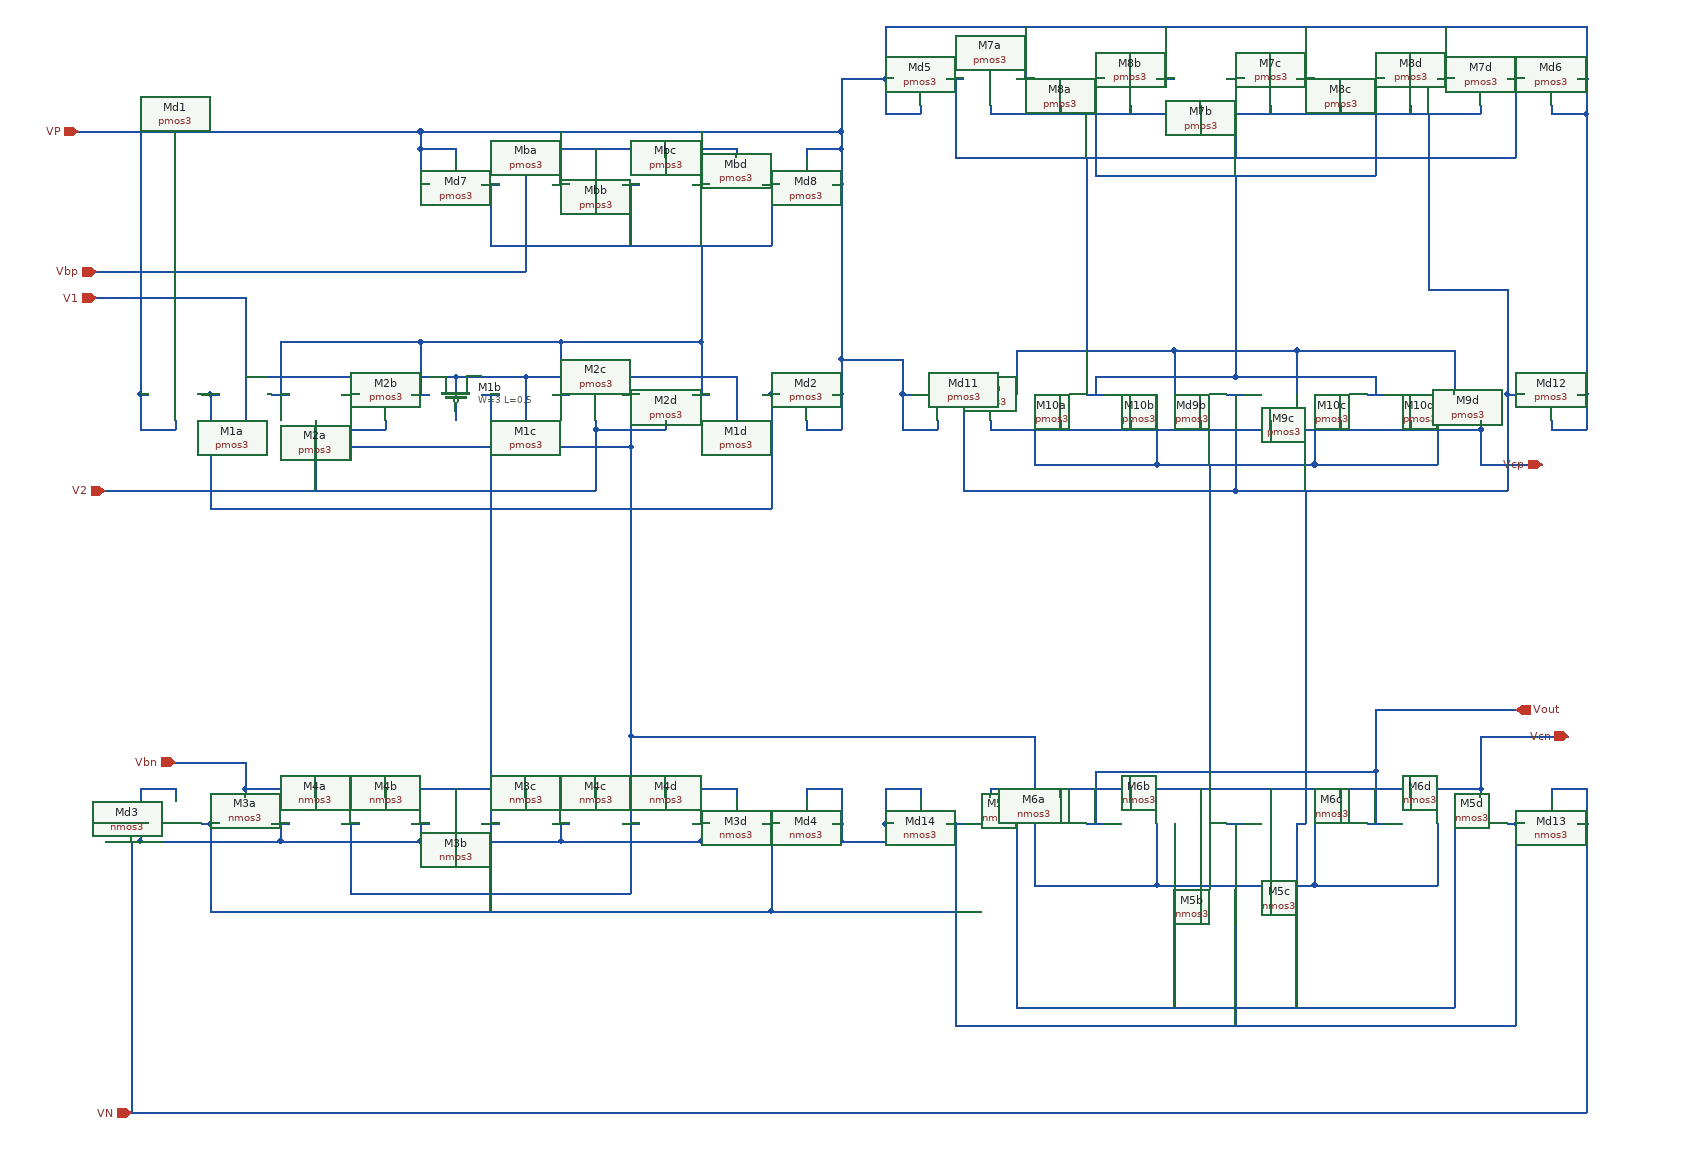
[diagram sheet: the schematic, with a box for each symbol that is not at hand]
v {xschem version=2.9.9 file_version=1.2 }
G {}
K {}
V {}
S {}
E {}
N 240 -350 250 -350 { lab=#net1}
N 280 -390 280 -380 { lab=Vbn}
N 280 -390 840 -390 { lab=Vbn}
N 840 -390 840 -380 { lab=Vbn}
N 760 -390 760 -380 { lab=Vbn}
N 680 -390 680 -380 { lab=Vbn}
N 600 -390 600 -380 { lab=Vbn}
N 520 -390 520 -380 { lab=Vbn}
N 440 -390 440 -380 { lab=Vbn}
N 360 -390 360 -380 { lab=Vbn}
N 310 -350 330 -350 { lab=VP}
N 390 -350 410 -350 { lab=#net2}
N 470 -350 490 -350 { lab=VP}
N 550 -350 570 -350 { lab=#net1}
N 630 -350 650 -350 { lab=VP}
N 710 -350 730 -350 { lab=#net2}
N 790 -350 810 -350 { lab=VP}
N 240 -250 870 -250 { lab=#net1}
N 240 -350 240 -250 { lab=#net1}
N 870 -350 880 -350 { lab=#net1}
N 880 -350 880 -250 { lab=#net1}
N 870 -250 880 -250 { lab=#net1}
N 400 -350 400 -270 { lab=#net2}
N 720 -350 720 -270 { lab=#net2}
N 560 -350 560 -250 { lab=#net1}
N 280 -420 280 -390 { lab=Vbn}
N 200 -420 280 -420 { lab=Vbn}
N 400 -270 720 -270 { lab=#net2}
N 230 -350 240 -350 { lab=#net1}
N 200 -390 200 -380 { lab=VP}
N 160 -390 200 -390 { lab=VP}
N 160 -390 160 -350 { lab=VP}
N 160 -350 170 -350 { lab=VP}
N 160 -350 160 -330 { lab=VP}
N 880 -350 890 -350 { lab=#net1}
N 950 -350 960 -350 { lab=VP}
N 960 -390 960 -350 { lab=VP}
N 920 -390 960 -390 { lab=VP}
N 920 -390 920 -380 { lab=VP}
N 960 -350 960 -330 { lab=VP}
N 1090 -350 1100 -350 { lab=#net1}
N 1130 -390 1130 -380 { lab=Vcn}
N 1130 -390 1690 -390 { lab=Vcn}
N 1690 -390 1690 -380 { lab=Vcn}
N 1610 -390 1610 -380 { lab=Vcn}
N 1530 -390 1530 -380 { lab=Vcn}
N 1450 -390 1450 -380 { lab=Vcn}
N 1370 -390 1370 -380 { lab=Vcn}
N 1290 -390 1290 -380 { lab=Vcn}
N 1210 -390 1210 -380 { lab=Vcn}
N 1720 -350 1730 -350 { lab=#net1}
N 1080 -350 1090 -350 { lab=#net1}
N 1050 -390 1050 -380 { lab=VP}
N 1010 -390 1050 -390 { lab=VP}
N 1010 -390 1010 -350 { lab=VP}
N 1010 -350 1020 -350 { lab=VP}
N 1010 -350 1010 -330 { lab=VP}
N 1730 -350 1740 -350 { lab=#net1}
N 1800 -350 1810 -350 { lab=VP}
N 1810 -390 1810 -350 { lab=VP}
N 1770 -390 1810 -390 { lab=VP}
N 1770 -390 1770 -380 { lab=VP}
N 1810 -350 1810 -330 { lab=VP}
N 1160 -350 1160 -320 { lab=#net3}
N 1660 -350 1660 -320 { lab=#net3}
N 1090 -350 1090 -130 { lab=#net1}
N 1090 -130 1090 -120 { lab=#net1}
N 1160 -320 1160 -140 { lab=#net3}
N 1660 -320 1660 -140 { lab=#net3}
N 1160 -140 1660 -140 { lab=#net3}
N 1400 -350 1420 -350 { lab=#net1}
N 1240 -350 1260 -350 { lab=Vout}
N 1560 -350 1580 -350 { lab=Vout}
N 1320 -350 1320 -280 { lab=#net2}
N 1180 -280 1320 -280 { lab=#net2}
N 1180 -350 1180 -280 { lab=#net2}
N 1180 -450 1180 -350 { lab=#net2}
N 1690 -450 1690 -390 { lab=Vcn}
N 1690 -450 1790 -450 { lab=Vcn}
N 1500 -350 1500 -280 { lab=#net2}
N 1500 -280 1640 -280 { lab=#net2}
N 1640 -350 1640 -280 { lab=#net2}
N 1320 -280 1500 -280 { lab=#net2}
N 1570 -410 1570 -350 { lab=Vout}
N 1250 -410 1570 -410 { lab=Vout}
N 1250 -410 1250 -350 { lab=Vout}
N 1030 -450 1090 -450 { lab=#net2}
N 1490 -570 1490 -520 { lab=#net3}
N 1570 -480 1570 -410 { lab=Vout}
N 1570 -480 1730 -480 { lab=Vout}
N 1730 -350 1730 -120 { lab=#net1}
N 1090 -120 1730 -120 { lab=#net1}
N 720 -450 1030 -450 { lab=#net2}
N 720 -450 720 -350 { lab=#net2}
N 1130 -810 1130 -800 { lab=Vcp}
N 1210 -810 1210 -800 { lab=Vcp}
N 1290 -810 1290 -800 { lab=Vcp}
N 1370 -810 1370 -800 { lab=Vcp}
N 1450 -810 1450 -800 { lab=Vcp}
N 1530 -810 1530 -800 { lab=Vcp}
N 1610 -810 1610 -800 { lab=Vcp}
N 1690 -810 1690 -800 { lab=Vcp}
N 1130 -800 1690 -800 { lab=Vcp}
N 1400 -840 1420 -840 { lab=#net3}
N 1240 -840 1260 -840 { lab=#net4}
N 1560 -840 1580 -840 { lab=#net4}
N 1320 -840 1320 -760 { lab=Vout}
N 1320 -760 1500 -760 { lab=Vout}
N 1500 -840 1500 -760 { lab=Vout}
N 1180 -840 1180 -760 { lab=Vout}
N 1180 -760 1320 -760 { lab=Vout}
N 1500 -760 1640 -760 { lab=Vout}
N 1640 -840 1640 -760 { lab=Vout}
N 1250 -860 1250 -840 { lab=#net4}
N 1250 -860 1410 -860 { lab=#net4}
N 1410 -860 1570 -860 { lab=#net4}
N 1570 -860 1570 -840 { lab=#net4}
N 1410 -950 1410 -860 { lab=#net4}
N 1340 -350 1340 -140 { lab=#net3}
N 1480 -350 1480 -140 { lab=#net3}
N 1410 -350 1410 -120 { lab=#net1}
N 1480 -350 1490 -350 { lab=#net3}
N 1490 -520 1490 -350 { lab=#net3}
N 880 -250 1090 -250 { lab=#net1}
N 1090 -450 1180 -450 { lab=#net2}
N 1410 -840 1410 -780 { lab=#net3}
N 1720 -840 1720 -780 { lab=#net3}
N 1480 -890 1480 -840 { lab=#net5}
N 1480 -890 1660 -890 { lab=#net5}
N 1660 -890 1660 -840 { lab=#net5}
N 1340 -890 1340 -840 { lab=#net5}
N 1340 -890 1480 -890 { lab=#net5}
N 1100 -840 1100 -780 { lab=#net3}
N 1160 -890 1160 -840 { lab=#net5}
N 1160 -890 1340 -890 { lab=#net5}
N 1100 -780 1100 -730 { lab=#net3}
N 1100 -730 1410 -730 { lab=#net3}
N 1410 -730 1720 -730 { lab=#net3}
N 1720 -780 1720 -730 { lab=#net3}
N 1410 -780 1410 -730 { lab=#net3}
N 1380 -760 1380 -680 { lab=Vout}
N 1490 -730 1490 -640 { lab=#net3}
N 1690 -800 1690 -760 { lab=Vcp}
N 1690 -760 1760 -760 { lab=Vcp}
N 1070 -810 1070 -800 { lab=VP}
N 1030 -800 1070 -800 { lab=VP}
N 1030 -840 1030 -800 { lab=VP}
N 1030 -840 1040 -840 { lab=VP}
N 1030 -880 1030 -840 { lab=VP}
N 1720 -840 1740 -840 { lab=#net3}
N 1770 -810 1770 -800 { lab=VP}
N 1770 -800 1810 -800 { lab=VP}
N 1810 -840 1810 -800 { lab=VP}
N 1800 -840 1810 -840 { lab=VP}
N 1810 -860 1810 -840 { lab=VP}
N 1810 -880 1810 -860 { lab=VP}
N 1380 -670 1380 -410 { lab=Vout}
N 1380 -680 1380 -670 { lab=Vout}
N 1490 -640 1490 -570 { lab=#net3}
N 1720 -930 1720 -840 { lab=#net3}
N 1720 -960 1720 -930 { lab=#net3}
N 1240 -1040 1240 -890 { lab=#net5}
N 1400 -1200 1420 -1200 { lab=#net5}
N 1320 -1200 1340 -1200 { lab=VP}
N 1240 -1200 1260 -1200 { lab=#net4}
N 1160 -1200 1180 -1200 { lab=VP}
N 1480 -1200 1500 -1200 { lab=VP}
N 1560 -1200 1580 -1200 { lab=#net4}
N 1640 -1200 1660 -1200 { lab=VP}
N 1130 -1170 1130 -1160 { lab=#net3}
N 1130 -1160 1690 -1160 { lab=#net3}
N 1690 -1170 1690 -1160 { lab=#net3}
N 1610 -1170 1610 -1160 { lab=#net3}
N 1530 -1170 1530 -1160 { lab=#net3}
N 1450 -1170 1450 -1160 { lab=#net3}
N 1370 -1170 1370 -1160 { lab=#net3}
N 1290 -1170 1290 -1160 { lab=#net3}
N 1210 -1170 1210 -1160 { lab=#net3}
N 1170 -1260 1170 -1200 { lab=VP}
N 1330 -1260 1330 -1200 { lab=VP}
N 1490 -1260 1490 -1200 { lab=VP}
N 1650 -1260 1650 -1200 { lab=VP}
N 1570 -1200 1570 -1130 { lab=#net4}
N 1410 -1200 1410 -1130 { lab=#net5}
N 1250 -1200 1250 -1130 { lab=#net4}
N 1090 -1200 1100 -1200 { lab=#net5}
N 1090 -1200 1090 -1130 { lab=#net5}
N 1720 -1200 1730 -1200 { lab=#net5}
N 1730 -1200 1730 -1130 { lab=#net5}
N 1730 -1130 1730 -1110 { lab=#net5}
N 1090 -1110 1730 -1110 { lab=#net5}
N 1090 -1130 1090 -1110 { lab=#net5}
N 1410 -1130 1410 -1110 { lab=#net5}
N 1570 -1130 1570 -1090 { lab=#net4}
N 1250 -1090 1570 -1090 { lab=#net4}
N 1250 -1130 1250 -1090 { lab=#net4}
N 1410 -1090 1410 -1040 { lab=#net4}
N 1630 -1160 1630 -1030 { lab=#net3}
N 1080 -1200 1090 -1200 { lab=#net5}
N 1730 -1200 1740 -1200 { lab=#net5}
N 1050 -1170 1050 -1160 { lab=VP}
N 1010 -1160 1050 -1160 { lab=VP}
N 1010 -1200 1010 -1160 { lab=VP}
N 1010 -1200 1020 -1200 { lab=VP}
N 1010 -1250 1010 -1200 { lab=VP}
N 1770 -1170 1770 -1160 { lab=VP}
N 1770 -1160 1810 -1160 { lab=VP}
N 1810 -1200 1810 -1160 { lab=VP}
N 1800 -1200 1810 -1200 { lab=VP}
N 1810 -1260 1810 -1200 { lab=VP}
N 1630 -1030 1630 -960 { lab=#net3}
N 1630 -960 1720 -960 { lab=#net3}
N 1410 -1040 1410 -950 { lab=#net4}
N 1240 -1110 1240 -1040 { lab=#net5}
N 550 -840 570 -840 { lab=#net1}
N 470 -840 490 -840 { lab=#net6}
N 390 -840 410 -840 { lab=#net2}
N 310 -840 330 -840 { lab=#net6}
N 630 -840 650 -840 { lab=#net6}
N 710 -840 730 -840 { lab=#net2}
N 790 -840 810 -840 { lab=#net6}
N 760 -810 760 -800 { lab=V2}
N 680 -810 680 -800 { lab=V2}
N 440 -810 440 -800 { lab=V2}
N 360 -810 360 -800 { lab=V2}
N 320 -900 320 -840 { lab=#net6}
N 480 -900 480 -840 { lab=#net6}
N 640 -900 640 -840 { lab=#net6}
N 800 -900 800 -840 { lab=#net6}
N 240 -840 250 -840 { lab=#net1}
N 870 -840 880 -840 { lab=#net1}
N 230 -840 240 -840 { lab=#net1}
N 880 -840 890 -840 { lab=#net1}
N 200 -810 200 -800 { lab=VP}
N 160 -800 200 -800 { lab=VP}
N 160 -840 160 -800 { lab=VP}
N 160 -840 170 -840 { lab=VP}
N 920 -810 920 -800 { lab=VP}
N 920 -800 960 -800 { lab=VP}
N 960 -840 960 -800 { lab=VP}
N 950 -840 960 -840 { lab=VP}
N 360 -800 440 -800 { lab=V2}
N 680 -800 760 -800 { lab=V2}
N 280 -950 280 -810 { lab=V1}
N 110 -950 280 -950 { lab=V1}
N 680 -800 680 -730 { lab=V2}
N 120 -730 680 -730 { lab=V2}
N 360 -800 360 -730 { lab=V2}
N 320 -900 480 -900 { lab=#net6}
N 480 -900 640 -900 { lab=#net6}
N 640 -900 800 -900 { lab=#net6}
N 240 -840 240 -790 { lab=#net1}
N 600 -860 600 -810 { lab=V1}
N 520 -860 600 -860 { lab=V1}
N 560 -840 560 -790 { lab=#net1}
N 880 -840 880 -790 { lab=#net1}
N 400 -840 400 -780 { lab=#net2}
N 400 -780 720 -780 { lab=#net2}
N 720 -840 720 -780 { lab=#net2}
N 240 -790 240 -760 { lab=#net1}
N 240 -760 240 -710 { lab=#net1}
N 240 -710 880 -710 { lab=#net1}
N 880 -790 880 -710 { lab=#net1}
N 720 -780 720 -640 { lab=#net2}
N 560 -790 560 -710 { lab=#net1}
N 960 -880 960 -840 { lab=VP}
N 160 -880 160 -840 { lab=VP}
N 520 -860 520 -820 { lab=V1}
N 840 -860 840 -810 { lab=V1}
N 600 -860 840 -860 { lab=V1}
N 280 -860 520 -860 { lab=V1}
N 720 -640 720 -620 { lab=#net2}
N 720 -620 720 -450 { lab=#net2}
N 560 -630 560 -350 { lab=#net1}
N 560 -710 560 -630 { lab=#net1}
N 520 -1120 520 -1110 { lab=VP}
N 600 -1120 600 -1110 { lab=Vbp}
N 680 -1120 680 -1110 { lab=Vbp}
N 760 -1120 760 -1110 { lab=Vbp}
N 840 -1120 840 -1110 { lab=Vbp}
N 600 -1120 840 -1120 { lab=Vbp}
N 630 -1080 650 -1080 { lab=VP}
N 710 -1080 730 -1080 { lab=#net6}
N 790 -1080 810 -1080 { lab=VP}
N 870 -1080 890 -1080 { lab=#net6}
N 550 -1080 570 -1080 { lab=#net6}
N 480 -1120 520 -1120 { lab=VP}
N 480 -1120 480 -1080 { lab=VP}
N 480 -1080 490 -1080 { lab=VP}
N 920 -1120 920 -1110 { lab=VP}
N 920 -1120 960 -1120 { lab=VP}
N 960 -1120 960 -1080 { lab=VP}
N 950 -1080 960 -1080 { lab=VP}
N 720 -1080 720 -1060 { lab=#net6}
N 800 -1140 800 -1080 { lab=VP}
N 640 -1130 640 -1080 { lab=VP}
N 560 -1080 560 -1030 { lab=#net6}
N 880 -1080 880 -1030 { lab=#net6}
N 960 -1140 960 -1120 { lab=VP}
N 480 -1140 480 -1120 { lab=VP}
N 640 -1140 640 -1130 { lab=VP}
N 560 -1030 560 -1010 { lab=#net6}
N 560 -1010 880 -1010 { lab=#net6}
N 880 -1030 880 -1010 { lab=#net6}
N 720 -1060 720 -1010 { lab=#net6}
N 480 -980 600 -980 { lab=Vbp}
N 600 -1110 600 -980 { lab=Vbp}
N 800 -1010 800 -900 { lab=#net6}
N 110 -980 480 -980 { lab=Vbp}
N 520 -820 520 -810 { lab=V1}
N 520 -860 520 -810 { lab=V1}
N 550 -840 560 -840 { lab=#net1}
N 480 -840 490 -840 { lab=#net6}
N 960 -880 1030 -880 { lab=VP}
N 960 -1080 960 -880 { lab=VP}
N 480 -1140 960 -1140 { lab=VP}
N 960 -1200 960 -1140 { lab=VP}
N 960 -1200 1010 -1200 { lab=VP}
N 1010 -1260 1810 -1260 { lab=VP}
N 1010 -1260 1010 -1250 { lab=VP}
N 1810 -1160 1810 -880 { lab=VP}
N 90 -1140 480 -1140 { lab=VP}
N 160 -1140 160 -880 { lab=VP}
N 960 -330 1010 -330 { lab=VP}
N 800 -330 960 -330 { lab=VP}
N 800 -350 800 -330 { lab=VP}
N 640 -330 800 -330 { lab=VP}
N 640 -350 640 -330 { lab=VP}
N 480 -330 640 -330 { lab=VP}
N 480 -350 480 -330 { lab=VP}
N 320 -330 480 -330 { lab=VP}
N 320 -350 320 -330 { lab=VP}
N 160 -330 320 -330 { lab=VP}
N 120 -330 160 -330 { lab=VP}
N 1810 -330 1810 -240 { lab=VP}
N 1810 -240 1810 -20 { lab=VP}
N 150 -20 1810 -20 { lab=VP}
N 150 -330 150 -20 { lab=VP}
C {devices/opin.sym} 1730 -480 0 0 {name=p8 lab=Vout}
C {madvlsi/nmos3.sym} 280 -350 1 0 {name=M3a
L=0.5
W=3
body=GND
nf=1
mult=1
ad="'int((nf+1)/2) * W/nf * 0.29'" 
pd="'2*int((nf+1)/2) * (W/nf + 0.29)'"
as="'int((nf+2)/2) * W/nf * 0.29'" 
ps="'2*int((nf+2)/2) * (W/nf + 0.29)'"
nrd="'0.29 / W'" nrs="'0.29 / W'"
sa=0 sb=0 sd=0
model=nfet_01v8
spiceprefix=X
}
C {madvlsi/nmos3.sym} 360 -350 1 0 {name=M4a
L=0.5
W=3
body=GND
nf=1
mult=1
ad="'int((nf+1)/2) * W/nf * 0.29'" 
pd="'2*int((nf+1)/2) * (W/nf + 0.29)'"
as="'int((nf+2)/2) * W/nf * 0.29'" 
ps="'2*int((nf+2)/2) * (W/nf + 0.29)'"
nrd="'0.29 / W'" nrs="'0.29 / W'"
sa=0 sb=0 sd=0
model=nfet_01v8
spiceprefix=X
}
C {madvlsi/nmos3.sym} 440 -350 1 0 {name=M4b
L=0.5
W=3
body=GND
nf=1
mult=1
ad="'int((nf+1)/2) * W/nf * 0.29'" 
pd="'2*int((nf+1)/2) * (W/nf + 0.29)'"
as="'int((nf+2)/2) * W/nf * 0.29'" 
ps="'2*int((nf+2)/2) * (W/nf + 0.29)'"
nrd="'0.29 / W'" nrs="'0.29 / W'"
sa=0 sb=0 sd=0
model=nfet_01v8
spiceprefix=X
}
C {madvlsi/nmos3.sym} 520 -350 1 0 {name=M3b
L=0.5
W=3
body=GND
nf=1
mult=1
ad="'int((nf+1)/2) * W/nf * 0.29'" 
pd="'2*int((nf+1)/2) * (W/nf + 0.29)'"
as="'int((nf+2)/2) * W/nf * 0.29'" 
ps="'2*int((nf+2)/2) * (W/nf + 0.29)'"
nrd="'0.29 / W'" nrs="'0.29 / W'"
sa=0 sb=0 sd=0
model=nfet_01v8
spiceprefix=X
}
C {madvlsi/nmos3.sym} 600 -350 1 0 {name=M3c
L=0.5
W=3
body=GND
nf=1
mult=1
ad="'int((nf+1)/2) * W/nf * 0.29'" 
pd="'2*int((nf+1)/2) * (W/nf + 0.29)'"
as="'int((nf+2)/2) * W/nf * 0.29'" 
ps="'2*int((nf+2)/2) * (W/nf + 0.29)'"
nrd="'0.29 / W'" nrs="'0.29 / W'"
sa=0 sb=0 sd=0
model=nfet_01v8
spiceprefix=X
}
C {madvlsi/nmos3.sym} 680 -350 1 0 {name=M4c
L=0.5
W=3
body=GND
nf=1
mult=1
ad="'int((nf+1)/2) * W/nf * 0.29'" 
pd="'2*int((nf+1)/2) * (W/nf + 0.29)'"
as="'int((nf+2)/2) * W/nf * 0.29'" 
ps="'2*int((nf+2)/2) * (W/nf + 0.29)'"
nrd="'0.29 / W'" nrs="'0.29 / W'"
sa=0 sb=0 sd=0
model=nfet_01v8
spiceprefix=X
}
C {madvlsi/nmos3.sym} 760 -350 1 0 {name=M4d
L=0.5
W=3
body=GND
nf=1
mult=1
ad="'int((nf+1)/2) * W/nf * 0.29'" 
pd="'2*int((nf+1)/2) * (W/nf + 0.29)'"
as="'int((nf+2)/2) * W/nf * 0.29'" 
ps="'2*int((nf+2)/2) * (W/nf + 0.29)'"
nrd="'0.29 / W'" nrs="'0.29 / W'"
sa=0 sb=0 sd=0
model=nfet_01v8
spiceprefix=X
}
C {madvlsi/nmos3.sym} 840 -350 1 0 {name=M3d
L=0.5
W=3
body=GND
nf=1
mult=1
ad="'int((nf+1)/2) * W/nf * 0.29'" 
pd="'2*int((nf+1)/2) * (W/nf + 0.29)'"
as="'int((nf+2)/2) * W/nf * 0.29'" 
ps="'2*int((nf+2)/2) * (W/nf + 0.29)'"
nrd="'0.29 / W'" nrs="'0.29 / W'"
sa=0 sb=0 sd=0
model=nfet_01v8
spiceprefix=X
}
C {devices/ipin.sym} 200 -420 0 0 {name=p7 lab=Vbn}
C {madvlsi/nmos3.sym} 200 -350 1 0 {name=Md3
L=0.5
W=3
body=GND
nf=1
mult=1
ad="'int((nf+1)/2) * W/nf * 0.29'" 
pd="'2*int((nf+1)/2) * (W/nf + 0.29)'"
as="'int((nf+2)/2) * W/nf * 0.29'" 
ps="'2*int((nf+2)/2) * (W/nf + 0.29)'"
nrd="'0.29 / W'" nrs="'0.29 / W'"
sa=0 sb=0 sd=0
model=nfet_01v8
spiceprefix=X
}
C {madvlsi/nmos3.sym} 920 -350 1 0 {name=Md4
L=0.5
W=3
body=GND
nf=1
mult=1
ad="'int((nf+1)/2) * W/nf * 0.29'" 
pd="'2*int((nf+1)/2) * (W/nf + 0.29)'"
as="'int((nf+2)/2) * W/nf * 0.29'" 
ps="'2*int((nf+2)/2) * (W/nf + 0.29)'"
nrd="'0.29 / W'" nrs="'0.29 / W'"
sa=0 sb=0 sd=0
model=nfet_01v8
spiceprefix=X
}
C {madvlsi/nmos3.sym} 1130 -350 1 0 {name=M5a
L=0.5
W=3
body=GND
nf=1
mult=1
ad="'int((nf+1)/2) * W/nf * 0.29'" 
pd="'2*int((nf+1)/2) * (W/nf + 0.29)'"
as="'int((nf+2)/2) * W/nf * 0.29'" 
ps="'2*int((nf+2)/2) * (W/nf + 0.29)'"
nrd="'0.29 / W'" nrs="'0.29 / W'"
sa=0 sb=0 sd=0
model=nfet_01v8
spiceprefix=X
}
C {madvlsi/nmos3.sym} 1210 -350 1 0 {name=M6a
L=0.5
W=3
body=GND
nf=1
mult=1
ad="'int((nf+1)/2) * W/nf * 0.29'" 
pd="'2*int((nf+1)/2) * (W/nf + 0.29)'"
as="'int((nf+2)/2) * W/nf * 0.29'" 
ps="'2*int((nf+2)/2) * (W/nf + 0.29)'"
nrd="'0.29 / W'" nrs="'0.29 / W'"
sa=0 sb=0 sd=0
model=nfet_01v8
spiceprefix=X
}
C {madvlsi/nmos3.sym} 1290 -350 1 0 {name=M6b
L=0.5
W=3
body=GND
nf=1
mult=1
ad="'int((nf+1)/2) * W/nf * 0.29'" 
pd="'2*int((nf+1)/2) * (W/nf + 0.29)'"
as="'int((nf+2)/2) * W/nf * 0.29'" 
ps="'2*int((nf+2)/2) * (W/nf + 0.29)'"
nrd="'0.29 / W'" nrs="'0.29 / W'"
sa=0 sb=0 sd=0
model=nfet_01v8
spiceprefix=X
}
C {madvlsi/nmos3.sym} 1370 -350 1 0 {name=M5b
L=0.5
W=3
body=GND
nf=1
mult=1
ad="'int((nf+1)/2) * W/nf * 0.29'" 
pd="'2*int((nf+1)/2) * (W/nf + 0.29)'"
as="'int((nf+2)/2) * W/nf * 0.29'" 
ps="'2*int((nf+2)/2) * (W/nf + 0.29)'"
nrd="'0.29 / W'" nrs="'0.29 / W'"
sa=0 sb=0 sd=0
model=nfet_01v8
spiceprefix=X
}
C {madvlsi/nmos3.sym} 1450 -350 1 0 {name=M5c
L=0.5
W=3
body=GND
nf=1
mult=1
ad="'int((nf+1)/2) * W/nf * 0.29'" 
pd="'2*int((nf+1)/2) * (W/nf + 0.29)'"
as="'int((nf+2)/2) * W/nf * 0.29'" 
ps="'2*int((nf+2)/2) * (W/nf + 0.29)'"
nrd="'0.29 / W'" nrs="'0.29 / W'"
sa=0 sb=0 sd=0
model=nfet_01v8
spiceprefix=X
}
C {madvlsi/nmos3.sym} 1530 -350 1 0 {name=M6c
L=0.5
W=3
body=GND
nf=1
mult=1
ad="'int((nf+1)/2) * W/nf * 0.29'" 
pd="'2*int((nf+1)/2) * (W/nf + 0.29)'"
as="'int((nf+2)/2) * W/nf * 0.29'" 
ps="'2*int((nf+2)/2) * (W/nf + 0.29)'"
nrd="'0.29 / W'" nrs="'0.29 / W'"
sa=0 sb=0 sd=0
model=nfet_01v8
spiceprefix=X
}
C {madvlsi/nmos3.sym} 1610 -350 1 0 {name=M6d
L=0.5
W=3
body=GND
nf=1
mult=1
ad="'int((nf+1)/2) * W/nf * 0.29'" 
pd="'2*int((nf+1)/2) * (W/nf + 0.29)'"
as="'int((nf+2)/2) * W/nf * 0.29'" 
ps="'2*int((nf+2)/2) * (W/nf + 0.29)'"
nrd="'0.29 / W'" nrs="'0.29 / W'"
sa=0 sb=0 sd=0
model=nfet_01v8
spiceprefix=X
}
C {madvlsi/nmos3.sym} 1690 -350 1 0 {name=M5d
L=0.5
W=3
body=GND
nf=1
mult=1
ad="'int((nf+1)/2) * W/nf * 0.29'" 
pd="'2*int((nf+1)/2) * (W/nf + 0.29)'"
as="'int((nf+2)/2) * W/nf * 0.29'" 
ps="'2*int((nf+2)/2) * (W/nf + 0.29)'"
nrd="'0.29 / W'" nrs="'0.29 / W'"
sa=0 sb=0 sd=0
model=nfet_01v8
spiceprefix=X
}
C {madvlsi/nmos3.sym} 1050 -350 1 0 {name=Md14
L=0.5
W=3
body=GND
nf=1
mult=1
ad="'int((nf+1)/2) * W/nf * 0.29'" 
pd="'2*int((nf+1)/2) * (W/nf + 0.29)'"
as="'int((nf+2)/2) * W/nf * 0.29'" 
ps="'2*int((nf+2)/2) * (W/nf + 0.29)'"
nrd="'0.29 / W'" nrs="'0.29 / W'"
sa=0 sb=0 sd=0
model=nfet_01v8
spiceprefix=X
}
C {madvlsi/nmos3.sym} 1770 -350 1 0 {name=Md13
L=0.5
W=3
body=GND
nf=1
mult=1
ad="'int((nf+1)/2) * W/nf * 0.29'" 
pd="'2*int((nf+1)/2) * (W/nf + 0.29)'"
as="'int((nf+2)/2) * W/nf * 0.29'" 
ps="'2*int((nf+2)/2) * (W/nf + 0.29)'"
nrd="'0.29 / W'" nrs="'0.29 / W'"
sa=0 sb=0 sd=0
model=nfet_01v8
spiceprefix=X
}
C {devices/ipin.sym} 1790 -450 2 0 {name=p4 lab=Vcn}
C {madvlsi/pmos3.sym} 1130 -840 3 0 {name=M9a
L=0.5
W=3
body=VDD
nf=1
mult=1
ad="'int((nf+1)/2) * W/nf * 0.29'" 
pd="'2*int((nf+1)/2) * (W/nf + 0.29)'"
as="'int((nf+2)/2) * W/nf * 0.29'" 
ps="'2*int((nf+2)/2) * (W/nf + 0.29)'"
nrd="'0.29 / W'" nrs="'0.29 / W'"
sa=0 sb=0 sd=0
model=pfet_01v8
spiceprefix=X
}
C {madvlsi/pmos3.sym} 1210 -840 3 0 {name=M10a
L=0.5
W=3
body=VDD
nf=1
mult=1
ad="'int((nf+1)/2) * W/nf * 0.29'" 
pd="'2*int((nf+1)/2) * (W/nf + 0.29)'"
as="'int((nf+2)/2) * W/nf * 0.29'" 
ps="'2*int((nf+2)/2) * (W/nf + 0.29)'"
nrd="'0.29 / W'" nrs="'0.29 / W'"
sa=0 sb=0 sd=0
model=pfet_01v8
spiceprefix=X
}
C {madvlsi/pmos3.sym} 1290 -840 3 0 {name=M10b
L=0.5
W=3
body=VDD
nf=1
mult=1
ad="'int((nf+1)/2) * W/nf * 0.29'" 
pd="'2*int((nf+1)/2) * (W/nf + 0.29)'"
as="'int((nf+2)/2) * W/nf * 0.29'" 
ps="'2*int((nf+2)/2) * (W/nf + 0.29)'"
nrd="'0.29 / W'" nrs="'0.29 / W'"
sa=0 sb=0 sd=0
model=pfet_01v8
spiceprefix=X
}
C {madvlsi/pmos3.sym} 1370 -840 3 0 {name=Md9b
L=0.5
W=3
body=VDD
nf=1
mult=1
ad="'int((nf+1)/2) * W/nf * 0.29'" 
pd="'2*int((nf+1)/2) * (W/nf + 0.29)'"
as="'int((nf+2)/2) * W/nf * 0.29'" 
ps="'2*int((nf+2)/2) * (W/nf + 0.29)'"
nrd="'0.29 / W'" nrs="'0.29 / W'"
sa=0 sb=0 sd=0
model=pfet_01v8
spiceprefix=X
}
C {madvlsi/pmos3.sym} 1450 -840 3 0 {name=M9c
L=0.5
W=3
body=VDD
nf=1
mult=1
ad="'int((nf+1)/2) * W/nf * 0.29'" 
pd="'2*int((nf+1)/2) * (W/nf + 0.29)'"
as="'int((nf+2)/2) * W/nf * 0.29'" 
ps="'2*int((nf+2)/2) * (W/nf + 0.29)'"
nrd="'0.29 / W'" nrs="'0.29 / W'"
sa=0 sb=0 sd=0
model=pfet_01v8
spiceprefix=X
}
C {madvlsi/pmos3.sym} 1530 -840 3 0 {name=M10c
L=0.5
W=3
body=VDD
nf=1
mult=1
ad="'int((nf+1)/2) * W/nf * 0.29'" 
pd="'2*int((nf+1)/2) * (W/nf + 0.29)'"
as="'int((nf+2)/2) * W/nf * 0.29'" 
ps="'2*int((nf+2)/2) * (W/nf + 0.29)'"
nrd="'0.29 / W'" nrs="'0.29 / W'"
sa=0 sb=0 sd=0
model=pfet_01v8
spiceprefix=X
}
C {madvlsi/pmos3.sym} 1610 -840 3 0 {name=M10d
L=0.5
W=3
body=VDD
nf=1
mult=1
ad="'int((nf+1)/2) * W/nf * 0.29'" 
pd="'2*int((nf+1)/2) * (W/nf + 0.29)'"
as="'int((nf+2)/2) * W/nf * 0.29'" 
ps="'2*int((nf+2)/2) * (W/nf + 0.29)'"
nrd="'0.29 / W'" nrs="'0.29 / W'"
sa=0 sb=0 sd=0
model=pfet_01v8
spiceprefix=X
}
C {madvlsi/pmos3.sym} 1690 -840 3 0 {name=M9d
L=0.5
W=3
body=VDD
nf=1
mult=1
ad="'int((nf+1)/2) * W/nf * 0.29'" 
pd="'2*int((nf+1)/2) * (W/nf + 0.29)'"
as="'int((nf+2)/2) * W/nf * 0.29'" 
ps="'2*int((nf+2)/2) * (W/nf + 0.29)'"
nrd="'0.29 / W'" nrs="'0.29 / W'"
sa=0 sb=0 sd=0
model=pfet_01v8
spiceprefix=X
}
C {devices/ipin.sym} 1760 -760 2 0 {name=p5 lab=Vcp}
C {madvlsi/pmos3.sym} 1070 -840 3 0 {name=Md11
L=0.5
W=3
body=VDD
nf=1
mult=1
ad="'int((nf+1)/2) * W/nf * 0.29'" 
pd="'2*int((nf+1)/2) * (W/nf + 0.29)'"
as="'int((nf+2)/2) * W/nf * 0.29'" 
ps="'2*int((nf+2)/2) * (W/nf + 0.29)'"
nrd="'0.29 / W'" nrs="'0.29 / W'"
sa=0 sb=0 sd=0
model=pfet_01v8
spiceprefix=X
}
C {madvlsi/pmos3.sym} 1770 -840 3 0 {name=Md12
L=0.5
W=3
body=VDD
nf=1
mult=1
ad="'int((nf+1)/2) * W/nf * 0.29'" 
pd="'2*int((nf+1)/2) * (W/nf + 0.29)'"
as="'int((nf+2)/2) * W/nf * 0.29'" 
ps="'2*int((nf+2)/2) * (W/nf + 0.29)'"
nrd="'0.29 / W'" nrs="'0.29 / W'"
sa=0 sb=0 sd=0
model=pfet_01v8
spiceprefix=X
}
C {madvlsi/pmos3.sym} 1130 -1200 3 0 {name=M7a
L=0.5
W=3
body=VDD
nf=1
mult=1
ad="'int((nf+1)/2) * W/nf * 0.29'" 
pd="'2*int((nf+1)/2) * (W/nf + 0.29)'"
as="'int((nf+2)/2) * W/nf * 0.29'" 
ps="'2*int((nf+2)/2) * (W/nf + 0.29)'"
nrd="'0.29 / W'" nrs="'0.29 / W'"
sa=0 sb=0 sd=0
model=pfet_01v8
spiceprefix=X
}
C {madvlsi/pmos3.sym} 1210 -1200 3 0 {name=M8a
L=0.5
W=3
body=VDD
nf=1
mult=1
ad="'int((nf+1)/2) * W/nf * 0.29'" 
pd="'2*int((nf+1)/2) * (W/nf + 0.29)'"
as="'int((nf+2)/2) * W/nf * 0.29'" 
ps="'2*int((nf+2)/2) * (W/nf + 0.29)'"
nrd="'0.29 / W'" nrs="'0.29 / W'"
sa=0 sb=0 sd=0
model=pfet_01v8
spiceprefix=X
}
C {madvlsi/pmos3.sym} 1290 -1200 3 0 {name=M8b
L=0.5
W=3
body=VDD
nf=1
mult=1
ad="'int((nf+1)/2) * W/nf * 0.29'" 
pd="'2*int((nf+1)/2) * (W/nf + 0.29)'"
as="'int((nf+2)/2) * W/nf * 0.29'" 
ps="'2*int((nf+2)/2) * (W/nf + 0.29)'"
nrd="'0.29 / W'" nrs="'0.29 / W'"
sa=0 sb=0 sd=0
model=pfet_01v8
spiceprefix=X
}
C {madvlsi/pmos3.sym} 1370 -1200 3 0 {name=M7b
L=0.5
W=3
body=VDD
nf=1
mult=1
ad="'int((nf+1)/2) * W/nf * 0.29'" 
pd="'2*int((nf+1)/2) * (W/nf + 0.29)'"
as="'int((nf+2)/2) * W/nf * 0.29'" 
ps="'2*int((nf+2)/2) * (W/nf + 0.29)'"
nrd="'0.29 / W'" nrs="'0.29 / W'"
sa=0 sb=0 sd=0
model=pfet_01v8
spiceprefix=X
}
C {madvlsi/pmos3.sym} 1450 -1200 3 0 {name=M7c
L=0.5
W=3
body=VDD
nf=1
mult=1
ad="'int((nf+1)/2) * W/nf * 0.29'" 
pd="'2*int((nf+1)/2) * (W/nf + 0.29)'"
as="'int((nf+2)/2) * W/nf * 0.29'" 
ps="'2*int((nf+2)/2) * (W/nf + 0.29)'"
nrd="'0.29 / W'" nrs="'0.29 / W'"
sa=0 sb=0 sd=0
model=pfet_01v8
spiceprefix=X
}
C {madvlsi/pmos3.sym} 1530 -1200 3 0 {name=M8c
L=0.5
W=3
body=VDD
nf=1
mult=1
ad="'int((nf+1)/2) * W/nf * 0.29'" 
pd="'2*int((nf+1)/2) * (W/nf + 0.29)'"
as="'int((nf+2)/2) * W/nf * 0.29'" 
ps="'2*int((nf+2)/2) * (W/nf + 0.29)'"
nrd="'0.29 / W'" nrs="'0.29 / W'"
sa=0 sb=0 sd=0
model=pfet_01v8
spiceprefix=X
}
C {madvlsi/pmos3.sym} 1610 -1200 3 0 {name=M8d
L=0.5
W=3
body=VDD
nf=1
mult=1
ad="'int((nf+1)/2) * W/nf * 0.29'" 
pd="'2*int((nf+1)/2) * (W/nf + 0.29)'"
as="'int((nf+2)/2) * W/nf * 0.29'" 
ps="'2*int((nf+2)/2) * (W/nf + 0.29)'"
nrd="'0.29 / W'" nrs="'0.29 / W'"
sa=0 sb=0 sd=0
model=pfet_01v8
spiceprefix=X
}
C {madvlsi/pmos3.sym} 1690 -1200 3 0 {name=M7d
L=0.5
W=3
body=VDD
nf=1
mult=1
ad="'int((nf+1)/2) * W/nf * 0.29'" 
pd="'2*int((nf+1)/2) * (W/nf + 0.29)'"
as="'int((nf+2)/2) * W/nf * 0.29'" 
ps="'2*int((nf+2)/2) * (W/nf + 0.29)'"
nrd="'0.29 / W'" nrs="'0.29 / W'"
sa=0 sb=0 sd=0
model=pfet_01v8
spiceprefix=X
}
C {madvlsi/pmos3.sym} 1770 -1200 3 0 {name=Md6
L=0.5
W=3
body=VDD
nf=1
mult=1
ad="'int((nf+1)/2) * W/nf * 0.29'" 
pd="'2*int((nf+1)/2) * (W/nf + 0.29)'"
as="'int((nf+2)/2) * W/nf * 0.29'" 
ps="'2*int((nf+2)/2) * (W/nf + 0.29)'"
nrd="'0.29 / W'" nrs="'0.29 / W'"
sa=0 sb=0 sd=0
model=pfet_01v8
spiceprefix=X
}
C {madvlsi/pmos3.sym} 1050 -1200 3 0 {name=Md5
L=0.5
W=3
body=VDD
nf=1
mult=1
ad="'int((nf+1)/2) * W/nf * 0.29'" 
pd="'2*int((nf+1)/2) * (W/nf + 0.29)'"
as="'int((nf+2)/2) * W/nf * 0.29'" 
ps="'2*int((nf+2)/2) * (W/nf + 0.29)'"
nrd="'0.29 / W'" nrs="'0.29 / W'"
sa=0 sb=0 sd=0
model=pfet_01v8
spiceprefix=X
}
C {madvlsi/pmos3.sym} 280 -840 3 0 {name=M1a
L=0.5
W=3
body=VDD
nf=1
mult=1
ad="'int((nf+1)/2) * W/nf * 0.29'" 
pd="'2*int((nf+1)/2) * (W/nf + 0.29)'"
as="'int((nf+2)/2) * W/nf * 0.29'" 
ps="'2*int((nf+2)/2) * (W/nf + 0.29)'"
nrd="'0.29 / W'" nrs="'0.29 / W'"
sa=0 sb=0 sd=0
model=pfet_01v8
spiceprefix=X
}
C {madvlsi/pmos3.sym} 360 -840 3 0 {name=M2a
L=0.5
W=3
body=VDD
nf=1
mult=1
ad="'int((nf+1)/2) * W/nf * 0.29'" 
pd="'2*int((nf+1)/2) * (W/nf + 0.29)'"
as="'int((nf+2)/2) * W/nf * 0.29'" 
ps="'2*int((nf+2)/2) * (W/nf + 0.29)'"
nrd="'0.29 / W'" nrs="'0.29 / W'"
sa=0 sb=0 sd=0
model=pfet_01v8
spiceprefix=X
}
C {madvlsi/pmos3.sym} 440 -840 3 0 {name=M2b
L=0.5
W=3
body=VDD
nf=1
mult=1
ad="'int((nf+1)/2) * W/nf * 0.29'" 
pd="'2*int((nf+1)/2) * (W/nf + 0.29)'"
as="'int((nf+2)/2) * W/nf * 0.29'" 
ps="'2*int((nf+2)/2) * (W/nf + 0.29)'"
nrd="'0.29 / W'" nrs="'0.29 / W'"
sa=0 sb=0 sd=0
model=pfet_01v8
spiceprefix=X
}
C {madvlsi/pmos3.sym} 520 -840 3 0 {name=M1b
L=0.5
W=3
body=VDD
nf=1
mult=1
ad="'int((nf+1)/2) * W/nf * 0.29'" 
pd="'2*int((nf+1)/2) * (W/nf + 0.29)'"
as="'int((nf+2)/2) * W/nf * 0.29'" 
ps="'2*int((nf+2)/2) * (W/nf + 0.29)'"
nrd="'0.29 / W'" nrs="'0.29 / W'"
sa=0 sb=0 sd=0
model=pfet_01v8
spiceprefix=X
}
C {madvlsi/pmos3.sym} 600 -840 3 0 {name=M1c
L=0.5
W=3
body=VDD
nf=1
mult=1
ad="'int((nf+1)/2) * W/nf * 0.29'" 
pd="'2*int((nf+1)/2) * (W/nf + 0.29)'"
as="'int((nf+2)/2) * W/nf * 0.29'" 
ps="'2*int((nf+2)/2) * (W/nf + 0.29)'"
nrd="'0.29 / W'" nrs="'0.29 / W'"
sa=0 sb=0 sd=0
model=pfet_01v8
spiceprefix=X
}
C {madvlsi/pmos3.sym} 680 -840 3 0 {name=M2c
L=0.5
W=3
body=VDD
nf=1
mult=1
ad="'int((nf+1)/2) * W/nf * 0.29'" 
pd="'2*int((nf+1)/2) * (W/nf + 0.29)'"
as="'int((nf+2)/2) * W/nf * 0.29'" 
ps="'2*int((nf+2)/2) * (W/nf + 0.29)'"
nrd="'0.29 / W'" nrs="'0.29 / W'"
sa=0 sb=0 sd=0
model=pfet_01v8
spiceprefix=X
}
C {madvlsi/pmos3.sym} 760 -840 3 0 {name=M2d
L=0.5
W=3
body=VDD
nf=1
mult=1
ad="'int((nf+1)/2) * W/nf * 0.29'" 
pd="'2*int((nf+1)/2) * (W/nf + 0.29)'"
as="'int((nf+2)/2) * W/nf * 0.29'" 
ps="'2*int((nf+2)/2) * (W/nf + 0.29)'"
nrd="'0.29 / W'" nrs="'0.29 / W'"
sa=0 sb=0 sd=0
model=pfet_01v8
spiceprefix=X
}
C {madvlsi/pmos3.sym} 840 -840 3 0 {name=M1d
L=0.5
W=3
body=VDD
nf=1
mult=1
ad="'int((nf+1)/2) * W/nf * 0.29'" 
pd="'2*int((nf+1)/2) * (W/nf + 0.29)'"
as="'int((nf+2)/2) * W/nf * 0.29'" 
ps="'2*int((nf+2)/2) * (W/nf + 0.29)'"
nrd="'0.29 / W'" nrs="'0.29 / W'"
sa=0 sb=0 sd=0
model=pfet_01v8
spiceprefix=X
}
C {madvlsi/pmos3.sym} 920 -840 3 0 {name=Md2
L=0.5
W=3
body=VDD
nf=1
mult=1
ad="'int((nf+1)/2) * W/nf * 0.29'" 
pd="'2*int((nf+1)/2) * (W/nf + 0.29)'"
as="'int((nf+2)/2) * W/nf * 0.29'" 
ps="'2*int((nf+2)/2) * (W/nf + 0.29)'"
nrd="'0.29 / W'" nrs="'0.29 / W'"
sa=0 sb=0 sd=0
model=pfet_01v8
spiceprefix=X
}
C {madvlsi/pmos3.sym} 200 -840 3 0 {name=Md1
L=0.5
W=3
body=VDD
nf=1
mult=1
ad="'int((nf+1)/2) * W/nf * 0.29'" 
pd="'2*int((nf+1)/2) * (W/nf + 0.29)'"
as="'int((nf+2)/2) * W/nf * 0.29'" 
ps="'2*int((nf+2)/2) * (W/nf + 0.29)'"
nrd="'0.29 / W'" nrs="'0.29 / W'"
sa=0 sb=0 sd=0
model=pfet_01v8
spiceprefix=X
}
C {devices/ipin.sym} 110 -950 0 0 {name=p6 lab=V1}
C {devices/ipin.sym} 120 -730 0 0 {name=p9 lab=V2}
C {madvlsi/pmos3.sym} 600 -1080 1 0 {name=Mba
L=0.5
W=3
body=VDD
nf=1
mult=1
ad="'int((nf+1)/2) * W/nf * 0.29'" 
pd="'2*int((nf+1)/2) * (W/nf + 0.29)'"
as="'int((nf+2)/2) * W/nf * 0.29'" 
ps="'2*int((nf+2)/2) * (W/nf + 0.29)'"
nrd="'0.29 / W'" nrs="'0.29 / W'"
sa=0 sb=0 sd=0
model=pfet_01v8
spiceprefix=X
}
C {madvlsi/pmos3.sym} 680 -1080 1 0 {name=Mbb
L=0.5
W=3
body=VDD
nf=1
mult=1
ad="'int((nf+1)/2) * W/nf * 0.29'" 
pd="'2*int((nf+1)/2) * (W/nf + 0.29)'"
as="'int((nf+2)/2) * W/nf * 0.29'" 
ps="'2*int((nf+2)/2) * (W/nf + 0.29)'"
nrd="'0.29 / W'" nrs="'0.29 / W'"
sa=0 sb=0 sd=0
model=pfet_01v8
spiceprefix=X
}
C {madvlsi/pmos3.sym} 760 -1080 1 0 {name=Mbc
L=0.5
W=3
body=VDD
nf=1
mult=1
ad="'int((nf+1)/2) * W/nf * 0.29'" 
pd="'2*int((nf+1)/2) * (W/nf + 0.29)'"
as="'int((nf+2)/2) * W/nf * 0.29'" 
ps="'2*int((nf+2)/2) * (W/nf + 0.29)'"
nrd="'0.29 / W'" nrs="'0.29 / W'"
sa=0 sb=0 sd=0
model=pfet_01v8
spiceprefix=X
}
C {madvlsi/pmos3.sym} 840 -1080 1 0 {name=Mbd
L=0.5
W=3
body=VDD
nf=1
mult=1
ad="'int((nf+1)/2) * W/nf * 0.29'" 
pd="'2*int((nf+1)/2) * (W/nf + 0.29)'"
as="'int((nf+2)/2) * W/nf * 0.29'" 
ps="'2*int((nf+2)/2) * (W/nf + 0.29)'"
nrd="'0.29 / W'" nrs="'0.29 / W'"
sa=0 sb=0 sd=0
model=pfet_01v8
spiceprefix=X
}
C {madvlsi/pmos3.sym} 920 -1080 1 0 {name=Md8
L=0.5
W=3
body=VDD
nf=1
mult=1
ad="'int((nf+1)/2) * W/nf * 0.29'" 
pd="'2*int((nf+1)/2) * (W/nf + 0.29)'"
as="'int((nf+2)/2) * W/nf * 0.29'" 
ps="'2*int((nf+2)/2) * (W/nf + 0.29)'"
nrd="'0.29 / W'" nrs="'0.29 / W'"
sa=0 sb=0 sd=0
model=pfet_01v8
spiceprefix=X
}
C {madvlsi/pmos3.sym} 520 -1080 1 0 {name=Md7
L=0.5
W=3
body=VDD
nf=1
mult=1
ad="'int((nf+1)/2) * W/nf * 0.29'" 
pd="'2*int((nf+1)/2) * (W/nf + 0.29)'"
as="'int((nf+2)/2) * W/nf * 0.29'" 
ps="'2*int((nf+2)/2) * (W/nf + 0.29)'"
nrd="'0.29 / W'" nrs="'0.29 / W'"
sa=0 sb=0 sd=0
model=pfet_01v8
spiceprefix=X
}
C {devices/ipin.sym} 110 -980 0 0 {name=p1 lab=Vbp}
C {devices/iopin.sym} 90 -1140 2 0 {name=p2 lab=VP}
C {devices/iopin.sym} 150 -20 2 0 {name=p3 lab=VN}
